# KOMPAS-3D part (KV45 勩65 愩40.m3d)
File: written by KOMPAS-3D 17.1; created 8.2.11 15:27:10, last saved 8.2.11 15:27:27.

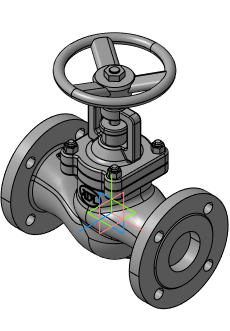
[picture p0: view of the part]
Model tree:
1. Плоскость XY
2. Плоскость ZX
3. Плоскость ZY
4. Ось X
5. Ось Y
6. Ось Z
7. Начало координат
8. Операция без истории:2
